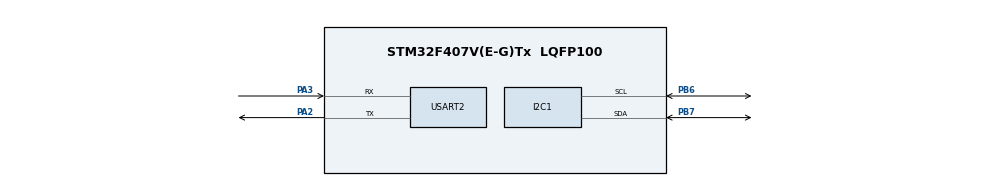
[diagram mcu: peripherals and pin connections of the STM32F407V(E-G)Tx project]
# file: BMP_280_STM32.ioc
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Mcu.Family=STM32F4
Mcu.Name=STM32F407V(E-G)Tx
Mcu.Package=LQFP100
NVIC.PriorityGroup=NVIC_PRIORITYGROUP_4
PA2.Mode=Asynchronous
PA2.Signal=USART2_TX
PA3.Mode=Asynchronous
PA3.Signal=USART2_RX
PB6.Mode=I2C
PB6.Signal=I2C1_SCL
PB7.Mode=I2C
PB7.Signal=I2C1_SDA
PH0-OSC_IN.Mode=HSE-External-Oscillator
PH0-OSC_IN.Signal=RCC_OSC_IN
PH1-OSC_OUT.Mode=HSE-External-Oscillator
PH1-OSC_OUT.Signal=RCC_OSC_OUT
ProjectManager.HeapSize=0x200
ProjectManager.StackSize=0x400
ProjectManager.TargetToolchain=STM32CubeIDE
RCC.48MHZClocksFreq_Value=84000000
RCC.AHBFreq_Value=168000000
RCC.APB1CLKDivider=RCC_HCLK_DIV8
RCC.APB1Freq_Value=21000000
RCC.APB1TimFreq_Value=42000000
RCC.APB2CLKDivider=RCC_HCLK_DIV4
RCC.APB2Freq_Value=42000000
RCC.APB2TimFreq_Value=84000000
RCC.CortexFreq_Value=168000000
RCC.HCLKFreq_Value=168000000
RCC.HSE_VALUE=8000000
RCC.HSI_VALUE=16000000
RCC.LSE_VALUE=32768
RCC.PLLM=8
RCC.PLLN=168
RCC.PLLSourceVirtual=RCC_PLLSOURCE_HSE
RCC.SYSCLKFreq_VALUE=168000000
RCC.SYSCLKSource=RCC_SYSCLKSOURCE_PLLCLK
RCC.VCOOutputFreq_Value=336000000
USART2.VirtualMode=VM_ASYNC
board=custom

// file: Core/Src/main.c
/* USER CODE BEGIN Header */
/**
 ******************************************************************************
 * @file           : main.c
 * @brief          : Main program body
 ******************************************************************************
 * @attention
 *
 * Copyright (c) 2024 STMicroelectronics.
 * All rights reserved.
 *
 * This software is licensed under terms that can be found in the LICENSE file
 * in the root directory of this software component.
 * If no LICENSE file comes with this software, it is provided AS-IS.
 *
 ******************************************************************************
 */
/* USER CODE END Header */
#include "main.h"
#include "i2c.h"
#include "usart.h"
#include "gpio.h"
#include "BMP280.h"
#include "string.h"
#include <stdio.h>
#include <stdlib.h>

/* USER CODE BEGIN Includes */
bmp280_t bmp280;

/* USER CODE END Includes */

void SystemClock_Config(void);

int main(void) {

	/* MCU Configuration--------------------------------------------------------*/

	/* Reset of all peripherals, Initializes the Flash interface and the Systick. */
	HAL_Init();

	/* Configure the system clock */
	SystemClock_Config();

	/* Initialize all configured peripherals */
	MX_GPIO_Init();
	MX_I2C1_Init();
	MX_USART2_UART_Init();
	/* USER CODE BEGIN 2 */
	char string[256];

	HAL_Delay(2000);
	BMP280_Init(&bmp280, F4_mode_normal, F5_t_sb_4sec, &hi2c1);
	BMP280_Calibration(&bmp280);
	BMP280_Read_All(&bmp280);

	/* USER CODE END 2 */

	/* Infinite loop */
	/* USER CODE BEGIN WHILE */
	while (1) {
		BMP280_Read_All(&bmp280);

		memset(&string, 0, strlen(string));

		strcat(string, "Temperature: ");
		utoa(bmp280.temperature, &string[strlen(string)], 3);
		strcat(string, " C\n");

		strcat(string, "Pressure: ");
		utoa(bmp280.pressure, &string[strlen(string)], 3);
		strcat(string, " Pa\n");

		strcat(string, "Altitude: ");
		utoa(bmp280.altitude, &string[strlen(string)], 3);
		strcat(string, " m\n");

		strcat(string, "Relative altitude: ");
		utoa(bmp280.altitude - bmp280.init_height, &string[strlen(string)], 3);
		strcat(string, " m\n\n\n");

		HAL_UART_Transmit(&huart2, (uint8_t*) &string, strlen(string),
				HAL_MAX_DELAY);

		/* USER CODE END WHILE */

	}
}

void SystemClock_Config(void) {
	RCC_OscInitTypeDef RCC_OscInitStruct = { 0 };
	RCC_ClkInitTypeDef RCC_ClkInitStruct = { 0 };

	/** Configure the main internal regulator output voltage
	 */
	__HAL_RCC_PWR_CLK_ENABLE();
	__HAL_PWR_VOLTAGESCALING_CONFIG(PWR_REGULATOR_VOLTAGE_SCALE1);

	/** Initializes the RCC Oscillators according to the specified parameters
	 * in the RCC_OscInitTypeDef structure.
	 */
	RCC_OscInitStruct.OscillatorType = RCC_OSCILLATORTYPE_HSE;
	RCC_OscInitStruct.HSEState = RCC_HSE_ON;
	RCC_OscInitStruct.PLL.PLLState = RCC_PLL_ON;
	RCC_OscInitStruct.PLL.PLLSource = RCC_PLLSOURCE_HSE;
	RCC_OscInitStruct.PLL.PLLM = 8;
	RCC_OscInitStruct.PLL.PLLN = 168;
	RCC_OscInitStruct.PLL.PLLP = RCC_PLLP_DIV2;
	RCC_OscInitStruct.PLL.PLLQ = 4;
	if (HAL_RCC_OscConfig(&RCC_OscInitStruct) != HAL_OK) {
		Error_Handler();
	}

	/** Initializes the CPU, AHB and APB buses clocks
	 */
	RCC_ClkInitStruct.ClockType = RCC_CLOCKTYPE_HCLK | RCC_CLOCKTYPE_SYSCLK
			| RCC_CLOCKTYPE_PCLK1 | RCC_CLOCKTYPE_PCLK2;
	RCC_ClkInitStruct.SYSCLKSource = RCC_SYSCLKSOURCE_PLLCLK;
	RCC_ClkInitStruct.AHBCLKDivider = RCC_SYSCLK_DIV1;
	RCC_ClkInitStruct.APB1CLKDivider = RCC_HCLK_DIV8;
	RCC_ClkInitStruct.APB2CLKDivider = RCC_HCLK_DIV4;

	if (HAL_RCC_ClockConfig(&RCC_ClkInitStruct, FLASH_LATENCY_5) != HAL_OK) {
		Error_Handler();
	}
}

void Error_Handler(void) {
	__disable_irq();
	while (1) {
	}
}
